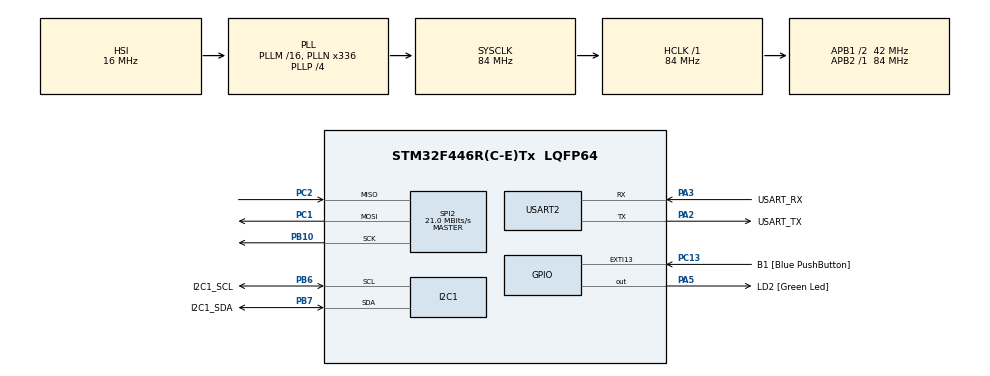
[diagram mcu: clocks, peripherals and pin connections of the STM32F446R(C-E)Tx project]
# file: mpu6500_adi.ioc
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Mcu.Family=STM32F4
Mcu.Name=STM32F446R(C-E)Tx
Mcu.Package=LQFP64
NVIC.PriorityGroup=NVIC_PRIORITYGROUP_0
PA13.GPIO_Label=TMS
PA13.Mode=Serial_Wire
PA13.Signal=SYS_JTMS-SWDIO
PA14.GPIO_Label=TCK
PA14.Mode=Serial_Wire
PA14.Signal=SYS_JTCK-SWCLK
PA2.GPIO_Label=USART_TX
PA2.Mode=Asynchronous
PA2.Signal=USART2_TX
PA3.GPIO_Label=USART_RX
PA3.Mode=Asynchronous
PA3.Signal=USART2_RX
PA5.GPIO_Label=LD2 [Green Led]
PA5.Signal=GPIO_Output
PB10.Mode=Full_Duplex_Master
PB10.Signal=SPI2_SCK
PB3.GPIO_Label=SWO
PB3.Signal=SYS_JTDO-SWO
PB6.GPIO_Label=I2C1_SCL
PB6.Mode=I2C
PB6.Signal=I2C1_SCL
PB7.GPIO_Label=I2C1_SDA
PB7.Mode=I2C
PB7.Signal=I2C1_SDA
PC1.Mode=Full_Duplex_Master
PC1.Signal=SPI2_MOSI
PC13.GPIO_Label=B1 [Blue PushButton]
PC13.GPIO_ModeDefaultEXTI=GPIO_MODE_IT_FALLING
PC13.Signal=GPXTI13
PC14-OSC32_IN.Mode=LSE-External-Oscillator
PC14-OSC32_IN.Signal=RCC_OSC32_IN
PC15-OSC32_OUT.Mode=LSE-External-Oscillator
PC15-OSC32_OUT.Signal=RCC_OSC32_OUT
PC2.Mode=Full_Duplex_Master
PC2.Signal=SPI2_MISO
PH0-OSC_IN.Mode=HSE-External-Oscillator
PH0-OSC_IN.Signal=RCC_OSC_IN
PH1-OSC_OUT.Mode=HSE-External-Oscillator
PH1-OSC_OUT.Signal=RCC_OSC_OUT
ProjectManager.HeapSize=0x200
ProjectManager.StackSize=0x400
ProjectManager.TargetToolchain=STM32CubeIDE
RCC.48MHZClocksFreq_Value=84000000
RCC.AHBFreq_Value=84000000
RCC.APB1CLKDivider=RCC_HCLK_DIV2
RCC.APB1Freq_Value=42000000
RCC.APB1TimFreq_Value=84000000
RCC.APB2Freq_Value=84000000
RCC.APB2TimFreq_Value=84000000
RCC.CortexFreq_Value=84000000
RCC.FLatency-AdvancedSettings=FLASH_LATENCY_2
RCC.HCLKFreq_Value=84000000
RCC.HSE_VALUE=8000000
RCC.HSI_VALUE=16000000
RCC.PLLN=336
RCC.PLLP=RCC_PLLP_DIV4
RCC.SYSCLKFreq_VALUE=84000000
RCC.SYSCLKSource=RCC_SYSCLKSOURCE_PLLCLK
RCC.USBFreq_Value=168000000
RCC.VCOOutputFreq_Value=336000000
SPI2.CalculateBaudRate=21.0 MBits/s
SPI2.Direction=SPI_DIRECTION_2LINES
SPI2.Mode=SPI_MODE_MASTER
SPI2.VirtualType=VM_MASTER
USART2.VirtualMode=VM_ASYNC
board=NUCLEO-F446RE

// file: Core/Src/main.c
/* USER CODE BEGIN Header */
/**
  ******************************************************************************
  * @file           : main.c
  * @brief          : Main program body
  ******************************************************************************
  * @attention
  *
  * Copyright (c) 2026 STMicroelectronics.
  * All rights reserved.
  *
  * This software is licensed under terms that can be found in the LICENSE file
  * in the root directory of this software component.
  * If no LICENSE file comes with this software, it is provided AS-IS.
  *
  ******************************************************************************
  */
/* USER CODE END Header */
#include "main.h"

/* USER CODE BEGIN Includes */
#include "mpu6500.h"
#include "ssd1306.h"
#include "graphics.h"
#include "i2c_recovery.h"
#include "attitude.h"
/* USER CODE END Includes */

I2C_HandleTypeDef hi2c1;

SPI_HandleTypeDef hspi2;

UART_HandleTypeDef huart2;

void SystemClock_Config(void);
static void MX_GPIO_Init(void);
static void MX_I2C1_Init(void);
static void MX_SPI2_Init(void);
static void MX_USART2_UART_Init(void);

int main(void)
{

  /* MCU Configuration--------------------------------------------------------*/

  /* Reset of all peripherals, Initializes the Flash interface and the Systick. */
  HAL_Init();

  /* Configure the system clock */
  SystemClock_Config();

  /* Initialize all configured peripherals */
  MX_GPIO_Init();
  MX_I2C1_Init();
  MX_SPI2_Init();
  MX_USART2_UART_Init();
  /* USER CODE BEGIN 2 */
  mpu6500_t imu1;
  ssd1306_spi_t display1;
  attitude_t attitude1;
  vec3f_t values;

  display1.config.handle = &hspi2;

  display1.config.rst_pin = SSD1306_RES_Pin;
  display1.config.rst_port = SSD1306_RES_GPIO_Port;

  display1.config.dc_pin = SSD1306_DC_Pin;
  display1.config.dc_port = SSD1306_DC_GPIO_Port;

  display1.config.cs_pin = SSD1306_CS_Pin;
  display1.config.cs_port = SSD1306_CS_GPIO_Port;

  attitude1.orientation.sign_x = IMU_POSITIVE_SIGN;
  attitude1.orientation.sign_y = IMU_POSITIVE_SIGN;
  attitude1.orientation.sign_z = IMU_POSITIVE_SIGN;

  attitude1.orientation.body_x = IMU_AXIS_X;
  attitude1.orientation.body_y = IMU_AXIS_Y;
  attitude1.orientation.body_z = IMU_AXIS_Z;

  volatile HAL_StatusTypeDef init_status = mpu6500_init(&imu1, &hi2c1, 0x68);
  if (init_status != HAL_OK){
	  i2c_bus_recover(
	       &hi2c1,
	       I2C1_SCL_GPIO_Port,
		   I2C1_SCL_Pin,
	       I2C1_SDA_GPIO_Port,
		   I2C1_SDA_Pin
	  );
  }

  volatile HAL_StatusTypeDef calib_status = mpu6050_calibrate_gyro(&imu1,
		  MPU6500_DEFAULT_CALIBRATION_SAMPLES,
		  MPU6500_DEFAULT_CALIBRATION_DELAY);

  ssd1306_init(&display1);
  draw_line(&display1, 25, 25, 110, 55);
  ssd1306_update(&display1);

  /* USER CODE END 2 */

  /* Infinite loop */
  while (1)
  {

    /* USER CODE BEGIN 3 */
	  volatile HAL_StatusTypeDef read_status = mpu6500_read_data(&imu1);

	  values.x = imu1.data.accel_x_g;
	  values.y = imu1.data.accel_y_g;
	  values.z = imu1.data.accel_z_g;

	  attitude_compute_pitch_roll(&attitude1, values);

  }
  /* USER CODE END 3 */
}

void SystemClock_Config(void)
{
  RCC_OscInitTypeDef RCC_OscInitStruct = {0};
  RCC_ClkInitTypeDef RCC_ClkInitStruct = {0};

  /** Configure the main internal regulator output voltage
  */
  __HAL_RCC_PWR_CLK_ENABLE();
  __HAL_PWR_VOLTAGESCALING_CONFIG(PWR_REGULATOR_VOLTAGE_SCALE3);

  /** Initializes the RCC Oscillators according to the specified parameters
  * in the RCC_OscInitTypeDef structure.
  */
  RCC_OscInitStruct.OscillatorType = RCC_OSCILLATORTYPE_HSI;
  RCC_OscInitStruct.HSIState = RCC_HSI_ON;
  RCC_OscInitStruct.HSICalibrationValue = RCC_HSICALIBRATION_DEFAULT;
  RCC_OscInitStruct.PLL.PLLState = RCC_PLL_ON;
  RCC_OscInitStruct.PLL.PLLSource = RCC_PLLSOURCE_HSI;
  RCC_OscInitStruct.PLL.PLLM = 16;
  RCC_OscInitStruct.PLL.PLLN = 336;
  RCC_OscInitStruct.PLL.PLLP = RCC_PLLP_DIV4;
  RCC_OscInitStruct.PLL.PLLQ = 2;
  RCC_OscInitStruct.PLL.PLLR = 2;
  if (HAL_RCC_OscConfig(&RCC_OscInitStruct) != HAL_OK)
  {
    Error_Handler();
  }

  /** Initializes the CPU, AHB and APB buses clocks
  */
  RCC_ClkInitStruct.ClockType = RCC_CLOCKTYPE_HCLK|RCC_CLOCKTYPE_SYSCLK
                              |RCC_CLOCKTYPE_PCLK1|RCC_CLOCKTYPE_PCLK2;
  RCC_ClkInitStruct.SYSCLKSource = RCC_SYSCLKSOURCE_PLLCLK;
  RCC_ClkInitStruct.AHBCLKDivider = RCC_SYSCLK_DIV1;
  RCC_ClkInitStruct.APB1CLKDivider = RCC_HCLK_DIV2;
  RCC_ClkInitStruct.APB2CLKDivider = RCC_HCLK_DIV1;

  if (HAL_RCC_ClockConfig(&RCC_ClkInitStruct, FLASH_LATENCY_2) != HAL_OK)
  {
    Error_Handler();
  }
}

static void MX_I2C1_Init(void)
{

  hi2c1.Instance = I2C1;
  hi2c1.Init.ClockSpeed = 100000;
  hi2c1.Init.DutyCycle = I2C_DUTYCYCLE_2;
  hi2c1.Init.OwnAddress1 = 0;
  hi2c1.Init.AddressingMode = I2C_ADDRESSINGMODE_7BIT;
  hi2c1.Init.DualAddressMode = I2C_DUALADDRESS_DISABLE;
  hi2c1.Init.OwnAddress2 = 0;
  hi2c1.Init.GeneralCallMode = I2C_GENERALCALL_DISABLE;
  hi2c1.Init.NoStretchMode = I2C_NOSTRETCH_DISABLE;
  if (HAL_I2C_Init(&hi2c1) != HAL_OK)
  {
    Error_Handler();
  }

}

static void MX_SPI2_Init(void)
{

  /* SPI2 parameter configuration*/
  hspi2.Instance = SPI2;
  hspi2.Init.Mode = SPI_MODE_MASTER;
  hspi2.Init.Direction = SPI_DIRECTION_2LINES;
  hspi2.Init.DataSize = SPI_DATASIZE_8BIT;
  hspi2.Init.CLKPolarity = SPI_POLARITY_LOW;
  hspi2.Init.CLKPhase = SPI_PHASE_1EDGE;
  hspi2.Init.NSS = SPI_NSS_SOFT;
  hspi2.Init.BaudRatePrescaler = SPI_BAUDRATEPRESCALER_2;
  hspi2.Init.FirstBit = SPI_FIRSTBIT_MSB;
  hspi2.Init.TIMode = SPI_TIMODE_DISABLE;
  hspi2.Init.CRCCalculation = SPI_CRCCALCULATION_DISABLE;
  hspi2.Init.CRCPolynomial = 10;
  if (HAL_SPI_Init(&hspi2) != HAL_OK)
  {
    Error_Handler();
  }

}

static void MX_USART2_UART_Init(void)
{

  huart2.Instance = USART2;
  huart2.Init.BaudRate = 115200;
  huart2.Init.WordLength = UART_WORDLENGTH_8B;
  huart2.Init.StopBits = UART_STOPBITS_1;
  huart2.Init.Parity = UART_PARITY_NONE;
  huart2.Init.Mode = UART_MODE_TX_RX;
  huart2.Init.HwFlowCtl = UART_HWCONTROL_NONE;
  huart2.Init.OverSampling = UART_OVERSAMPLING_16;
  if (HAL_UART_Init(&huart2) != HAL_OK)
  {
    Error_Handler();
  }

}

static void MX_GPIO_Init(void)
{
  GPIO_InitTypeDef GPIO_InitStruct = {0};

  /* GPIO Ports Clock Enable */
  __HAL_RCC_GPIOC_CLK_ENABLE();
  __HAL_RCC_GPIOH_CLK_ENABLE();
  __HAL_RCC_GPIOA_CLK_ENABLE();
  __HAL_RCC_GPIOB_CLK_ENABLE();

  /*Configure GPIO pin Output Level */
  HAL_GPIO_WritePin(GPIOA, LD2_Pin|SSD1306_RES_Pin|SSD1306_CS_Pin|SSD1306_DC_Pin, GPIO_PIN_RESET);

  /*Configure GPIO pin : B1_Pin */
  GPIO_InitStruct.Pin = B1_Pin;
  GPIO_InitStruct.Mode = GPIO_MODE_IT_FALLING;
  GPIO_InitStruct.Pull = GPIO_NOPULL;
  HAL_GPIO_Init(B1_GPIO_Port, &GPIO_InitStruct);

  /*Configure GPIO pins : LD2_Pin SSD1306_RES_Pin SSD1306_CS_Pin SSD1306_DC_Pin */
  GPIO_InitStruct.Pin = LD2_Pin|SSD1306_RES_Pin|SSD1306_CS_Pin|SSD1306_DC_Pin;
  GPIO_InitStruct.Mode = GPIO_MODE_OUTPUT_PP;
  GPIO_InitStruct.Pull = GPIO_NOPULL;
  GPIO_InitStruct.Speed = GPIO_SPEED_FREQ_LOW;
  HAL_GPIO_Init(GPIOA, &GPIO_InitStruct);

}

void Error_Handler(void)
{
  __disable_irq();
  while (1)
  {
  }
}
